VERSION 5.7 ;
BUSBITCHARS "[]" ;
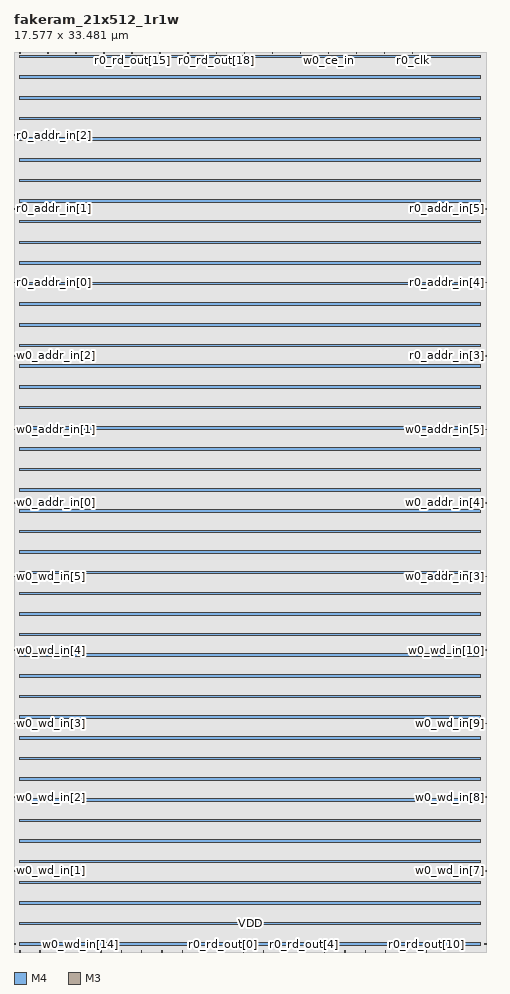
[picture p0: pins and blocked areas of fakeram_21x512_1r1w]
MACRO fakeram_21x512_1r1w
  FOREIGN fakeram_21x512_1r1w 0 0 ;
  SYMMETRY X Y R90 ;
  SIZE 17.577 BY 33.481 ;
  CLASS BLOCK ;
  PIN w0_wd_in[0]
    DIRECTION INPUT ;
    USE SIGNAL ;
    SHAPE ABUTMENT ;
    PORT
      LAYER M4 ;
      RECT 0.000 0.276 0.072 0.300 ;
    END
  END w0_wd_in[0]
  PIN w0_wd_in[1]
    DIRECTION INPUT ;
    USE SIGNAL ;
    SHAPE ABUTMENT ;
    PORT
      LAYER M4 ;
      RECT 0.000 3.012 0.072 3.036 ;
    END
  END w0_wd_in[1]
  PIN w0_wd_in[2]
    DIRECTION INPUT ;
    USE SIGNAL ;
    SHAPE ABUTMENT ;
    PORT
      LAYER M4 ;
      RECT 0.000 5.748 0.072 5.772 ;
    END
  END w0_wd_in[2]
  PIN w0_wd_in[3]
    DIRECTION INPUT ;
    USE SIGNAL ;
    SHAPE ABUTMENT ;
    PORT
      LAYER M4 ;
      RECT 0.000 8.484 0.072 8.508 ;
    END
  END w0_wd_in[3]
  PIN w0_wd_in[4]
    DIRECTION INPUT ;
    USE SIGNAL ;
    SHAPE ABUTMENT ;
    PORT
      LAYER M4 ;
      RECT 0.000 11.220 0.072 11.244 ;
    END
  END w0_wd_in[4]
  PIN w0_wd_in[5]
    DIRECTION INPUT ;
    USE SIGNAL ;
    SHAPE ABUTMENT ;
    PORT
      LAYER M4 ;
      RECT 0.000 13.956 0.072 13.980 ;
    END
  END w0_wd_in[5]
  PIN w0_wd_in[6]
    DIRECTION INPUT ;
    USE SIGNAL ;
    SHAPE ABUTMENT ;
    PORT
      LAYER M4 ;
      RECT 17.505 0.276 17.577 0.300 ;
    END
  END w0_wd_in[6]
  PIN w0_wd_in[7]
    DIRECTION INPUT ;
    USE SIGNAL ;
    SHAPE ABUTMENT ;
    PORT
      LAYER M4 ;
      RECT 17.505 3.012 17.577 3.036 ;
    END
  END w0_wd_in[7]
  PIN w0_wd_in[8]
    DIRECTION INPUT ;
    USE SIGNAL ;
    SHAPE ABUTMENT ;
    PORT
      LAYER M4 ;
      RECT 17.505 5.748 17.577 5.772 ;
    END
  END w0_wd_in[8]
  PIN w0_wd_in[9]
    DIRECTION INPUT ;
    USE SIGNAL ;
    SHAPE ABUTMENT ;
    PORT
      LAYER M4 ;
      RECT 17.505 8.484 17.577 8.508 ;
    END
  END w0_wd_in[9]
  PIN w0_wd_in[10]
    DIRECTION INPUT ;
    USE SIGNAL ;
    SHAPE ABUTMENT ;
    PORT
      LAYER M4 ;
      RECT 17.505 11.220 17.577 11.244 ;
    END
  END w0_wd_in[10]
  PIN w0_wd_in[11]
    DIRECTION INPUT ;
    USE SIGNAL ;
    SHAPE ABUTMENT ;
    PORT
      LAYER M3 ;
      RECT 0.207 0.000 0.225 0.054 ;
    END
  END w0_wd_in[11]
  PIN w0_wd_in[12]
    DIRECTION INPUT ;
    USE SIGNAL ;
    SHAPE ABUTMENT ;
    PORT
      LAYER M3 ;
      RECT 0.963 0.000 0.981 0.054 ;
    END
  END w0_wd_in[12]
  PIN w0_wd_in[13]
    DIRECTION INPUT ;
    USE SIGNAL ;
    SHAPE ABUTMENT ;
    PORT
      LAYER M3 ;
      RECT 1.719 0.000 1.737 0.054 ;
    END
  END w0_wd_in[13]
  PIN w0_wd_in[14]
    DIRECTION INPUT ;
    USE SIGNAL ;
    SHAPE ABUTMENT ;
    PORT
      LAYER M3 ;
      RECT 2.475 0.000 2.493 0.054 ;
    END
  END w0_wd_in[14]
  PIN w0_wd_in[15]
    DIRECTION INPUT ;
    USE SIGNAL ;
    SHAPE ABUTMENT ;
    PORT
      LAYER M3 ;
      RECT 3.231 0.000 3.249 0.054 ;
    END
  END w0_wd_in[15]
  PIN w0_wd_in[16]
    DIRECTION INPUT ;
    USE SIGNAL ;
    SHAPE ABUTMENT ;
    PORT
      LAYER M3 ;
      RECT 3.987 0.000 4.005 0.054 ;
    END
  END w0_wd_in[16]
  PIN w0_wd_in[17]
    DIRECTION INPUT ;
    USE SIGNAL ;
    SHAPE ABUTMENT ;
    PORT
      LAYER M3 ;
      RECT 4.743 0.000 4.761 0.054 ;
    END
  END w0_wd_in[17]
  PIN w0_wd_in[18]
    DIRECTION INPUT ;
    USE SIGNAL ;
    SHAPE ABUTMENT ;
    PORT
      LAYER M3 ;
      RECT 5.499 0.000 5.517 0.054 ;
    END
  END w0_wd_in[18]
  PIN w0_wd_in[19]
    DIRECTION INPUT ;
    USE SIGNAL ;
    SHAPE ABUTMENT ;
    PORT
      LAYER M3 ;
      RECT 6.255 0.000 6.273 0.054 ;
    END
  END w0_wd_in[19]
  PIN w0_wd_in[20]
    DIRECTION INPUT ;
    USE SIGNAL ;
    SHAPE ABUTMENT ;
    PORT
      LAYER M3 ;
      RECT 7.011 0.000 7.029 0.054 ;
    END
  END w0_wd_in[20]
  PIN r0_rd_out[0]
    DIRECTION OUTPUT ;
    USE SIGNAL ;
    SHAPE ABUTMENT ;
    PORT
      LAYER M3 ;
      RECT 7.767 0.000 7.785 0.054 ;
    END
  END r0_rd_out[0]
  PIN r0_rd_out[1]
    DIRECTION OUTPUT ;
    USE SIGNAL ;
    SHAPE ABUTMENT ;
    PORT
      LAYER M3 ;
      RECT 8.523 0.000 8.541 0.054 ;
    END
  END r0_rd_out[1]
  PIN r0_rd_out[2]
    DIRECTION OUTPUT ;
    USE SIGNAL ;
    SHAPE ABUTMENT ;
    PORT
      LAYER M3 ;
      RECT 9.279 0.000 9.297 0.054 ;
    END
  END r0_rd_out[2]
  PIN r0_rd_out[3]
    DIRECTION OUTPUT ;
    USE SIGNAL ;
    SHAPE ABUTMENT ;
    PORT
      LAYER M3 ;
      RECT 10.035 0.000 10.053 0.054 ;
    END
  END r0_rd_out[3]
  PIN r0_rd_out[4]
    DIRECTION OUTPUT ;
    USE SIGNAL ;
    SHAPE ABUTMENT ;
    PORT
      LAYER M3 ;
      RECT 10.791 0.000 10.809 0.054 ;
    END
  END r0_rd_out[4]
  PIN r0_rd_out[5]
    DIRECTION OUTPUT ;
    USE SIGNAL ;
    SHAPE ABUTMENT ;
    PORT
      LAYER M3 ;
      RECT 11.547 0.000 11.565 0.054 ;
    END
  END r0_rd_out[5]
  PIN r0_rd_out[6]
    DIRECTION OUTPUT ;
    USE SIGNAL ;
    SHAPE ABUTMENT ;
    PORT
      LAYER M3 ;
      RECT 12.303 0.000 12.321 0.054 ;
    END
  END r0_rd_out[6]
  PIN r0_rd_out[7]
    DIRECTION OUTPUT ;
    USE SIGNAL ;
    SHAPE ABUTMENT ;
    PORT
      LAYER M3 ;
      RECT 13.059 0.000 13.077 0.054 ;
    END
  END r0_rd_out[7]
  PIN r0_rd_out[8]
    DIRECTION OUTPUT ;
    USE SIGNAL ;
    SHAPE ABUTMENT ;
    PORT
      LAYER M3 ;
      RECT 13.815 0.000 13.833 0.054 ;
    END
  END r0_rd_out[8]
  PIN r0_rd_out[9]
    DIRECTION OUTPUT ;
    USE SIGNAL ;
    SHAPE ABUTMENT ;
    PORT
      LAYER M3 ;
      RECT 14.571 0.000 14.589 0.054 ;
    END
  END r0_rd_out[9]
  PIN r0_rd_out[10]
    DIRECTION OUTPUT ;
    USE SIGNAL ;
    SHAPE ABUTMENT ;
    PORT
      LAYER M3 ;
      RECT 15.327 0.000 15.345 0.054 ;
    END
  END r0_rd_out[10]
  PIN r0_rd_out[11]
    DIRECTION OUTPUT ;
    USE SIGNAL ;
    SHAPE ABUTMENT ;
    PORT
      LAYER M3 ;
      RECT 0.207 33.427 0.225 33.481 ;
    END
  END r0_rd_out[11]
  PIN r0_rd_out[12]
    DIRECTION OUTPUT ;
    USE SIGNAL ;
    SHAPE ABUTMENT ;
    PORT
      LAYER M3 ;
      RECT 1.251 33.427 1.269 33.481 ;
    END
  END r0_rd_out[12]
  PIN r0_rd_out[13]
    DIRECTION OUTPUT ;
    USE SIGNAL ;
    SHAPE ABUTMENT ;
    PORT
      LAYER M3 ;
      RECT 2.295 33.427 2.313 33.481 ;
    END
  END r0_rd_out[13]
  PIN r0_rd_out[14]
    DIRECTION OUTPUT ;
    USE SIGNAL ;
    SHAPE ABUTMENT ;
    PORT
      LAYER M3 ;
      RECT 3.339 33.427 3.357 33.481 ;
    END
  END r0_rd_out[14]
  PIN r0_rd_out[15]
    DIRECTION OUTPUT ;
    USE SIGNAL ;
    SHAPE ABUTMENT ;
    PORT
      LAYER M3 ;
      RECT 4.383 33.427 4.401 33.481 ;
    END
  END r0_rd_out[15]
  PIN r0_rd_out[16]
    DIRECTION OUTPUT ;
    USE SIGNAL ;
    SHAPE ABUTMENT ;
    PORT
      LAYER M3 ;
      RECT 5.427 33.427 5.445 33.481 ;
    END
  END r0_rd_out[16]
  PIN r0_rd_out[17]
    DIRECTION OUTPUT ;
    USE SIGNAL ;
    SHAPE ABUTMENT ;
    PORT
      LAYER M3 ;
      RECT 6.471 33.427 6.489 33.481 ;
    END
  END r0_rd_out[17]
  PIN r0_rd_out[18]
    DIRECTION OUTPUT ;
    USE SIGNAL ;
    SHAPE ABUTMENT ;
    PORT
      LAYER M3 ;
      RECT 7.515 33.427 7.533 33.481 ;
    END
  END r0_rd_out[18]
  PIN r0_rd_out[19]
    DIRECTION OUTPUT ;
    USE SIGNAL ;
    SHAPE ABUTMENT ;
    PORT
      LAYER M3 ;
      RECT 8.559 33.427 8.577 33.481 ;
    END
  END r0_rd_out[19]
  PIN r0_rd_out[20]
    DIRECTION OUTPUT ;
    USE SIGNAL ;
    SHAPE ABUTMENT ;
    PORT
      LAYER M3 ;
      RECT 9.603 33.427 9.621 33.481 ;
    END
  END r0_rd_out[20]
  PIN w0_addr_in[0]
    DIRECTION INPUT ;
    USE SIGNAL ;
    SHAPE ABUTMENT ;
    PORT
      LAYER M4 ;
      RECT 0.000 16.692 0.072 16.716 ;
    END
  END w0_addr_in[0]
  PIN w0_addr_in[1]
    DIRECTION INPUT ;
    USE SIGNAL ;
    SHAPE ABUTMENT ;
    PORT
      LAYER M4 ;
      RECT 0.000 19.428 0.072 19.452 ;
    END
  END w0_addr_in[1]
  PIN w0_addr_in[2]
    DIRECTION INPUT ;
    USE SIGNAL ;
    SHAPE ABUTMENT ;
    PORT
      LAYER M4 ;
      RECT 0.000 22.164 0.072 22.188 ;
    END
  END w0_addr_in[2]
  PIN w0_addr_in[3]
    DIRECTION INPUT ;
    USE SIGNAL ;
    SHAPE ABUTMENT ;
    PORT
      LAYER M4 ;
      RECT 17.505 13.956 17.577 13.980 ;
    END
  END w0_addr_in[3]
  PIN w0_addr_in[4]
    DIRECTION INPUT ;
    USE SIGNAL ;
    SHAPE ABUTMENT ;
    PORT
      LAYER M4 ;
      RECT 17.505 16.692 17.577 16.716 ;
    END
  END w0_addr_in[4]
  PIN w0_addr_in[5]
    DIRECTION INPUT ;
    USE SIGNAL ;
    SHAPE ABUTMENT ;
    PORT
      LAYER M4 ;
      RECT 17.505 19.428 17.577 19.452 ;
    END
  END w0_addr_in[5]
  PIN r0_addr_in[0]
    DIRECTION INPUT ;
    USE SIGNAL ;
    SHAPE ABUTMENT ;
    PORT
      LAYER M4 ;
      RECT 0.000 24.900 0.072 24.924 ;
    END
  END r0_addr_in[0]
  PIN r0_addr_in[1]
    DIRECTION INPUT ;
    USE SIGNAL ;
    SHAPE ABUTMENT ;
    PORT
      LAYER M4 ;
      RECT 0.000 27.636 0.072 27.660 ;
    END
  END r0_addr_in[1]
  PIN r0_addr_in[2]
    DIRECTION INPUT ;
    USE SIGNAL ;
    SHAPE ABUTMENT ;
    PORT
      LAYER M4 ;
      RECT 0.000 30.372 0.072 30.396 ;
    END
  END r0_addr_in[2]
  PIN r0_addr_in[3]
    DIRECTION INPUT ;
    USE SIGNAL ;
    SHAPE ABUTMENT ;
    PORT
      LAYER M4 ;
      RECT 17.505 22.164 17.577 22.188 ;
    END
  END r0_addr_in[3]
  PIN r0_addr_in[4]
    DIRECTION INPUT ;
    USE SIGNAL ;
    SHAPE ABUTMENT ;
    PORT
      LAYER M4 ;
      RECT 17.505 24.900 17.577 24.924 ;
    END
  END r0_addr_in[4]
  PIN r0_addr_in[5]
    DIRECTION INPUT ;
    USE SIGNAL ;
    SHAPE ABUTMENT ;
    PORT
      LAYER M4 ;
      RECT 17.505 27.636 17.577 27.660 ;
    END
  END r0_addr_in[5]
  PIN w0_we_in
    DIRECTION INPUT ;
    USE SIGNAL ;
    SHAPE ABUTMENT ;
    PORT
      LAYER M3 ;
      RECT 10.647 33.427 10.665 33.481 ;
    END
  END w0_we_in
  PIN w0_ce_in
    DIRECTION INPUT ;
    USE SIGNAL ;
    SHAPE ABUTMENT ;
    PORT
      LAYER M3 ;
      RECT 11.691 33.427 11.709 33.481 ;
    END
  END w0_ce_in
  PIN w0_clk
    DIRECTION INPUT ;
    USE SIGNAL ;
    SHAPE ABUTMENT ;
    PORT
      LAYER M3 ;
      RECT 12.735 33.427 12.753 33.481 ;
    END
  END w0_clk
  PIN r0_ce_in
    DIRECTION INPUT ;
    USE SIGNAL ;
    SHAPE ABUTMENT ;
    PORT
      LAYER M3 ;
      RECT 13.779 33.427 13.797 33.481 ;
    END
  END r0_ce_in
  PIN r0_clk
    DIRECTION INPUT ;
    USE SIGNAL ;
    SHAPE ABUTMENT ;
    PORT
      LAYER M3 ;
      RECT 14.823 33.427 14.841 33.481 ;
    END
  END r0_clk
  PIN VSS
    DIRECTION INOUT ;
    USE GROUND ;
    PORT
      LAYER M4 ;
      RECT 0.216 0.240 17.361 0.336 ;
      RECT 0.216 1.008 17.361 1.104 ;
      RECT 0.216 1.776 17.361 1.872 ;
      RECT 0.216 2.544 17.361 2.640 ;
      RECT 0.216 3.312 17.361 3.408 ;
      RECT 0.216 4.080 17.361 4.176 ;
      RECT 0.216 4.848 17.361 4.944 ;
      RECT 0.216 5.616 17.361 5.712 ;
      RECT 0.216 6.384 17.361 6.480 ;
      RECT 0.216 7.152 17.361 7.248 ;
      RECT 0.216 7.920 17.361 8.016 ;
      RECT 0.216 8.688 17.361 8.784 ;
      RECT 0.216 9.456 17.361 9.552 ;
      RECT 0.216 10.224 17.361 10.320 ;
      RECT 0.216 10.992 17.361 11.088 ;
      RECT 0.216 11.760 17.361 11.856 ;
      RECT 0.216 12.528 17.361 12.624 ;
      RECT 0.216 13.296 17.361 13.392 ;
      RECT 0.216 14.064 17.361 14.160 ;
      RECT 0.216 14.832 17.361 14.928 ;
      RECT 0.216 15.600 17.361 15.696 ;
      RECT 0.216 16.368 17.361 16.464 ;
      RECT 0.216 17.136 17.361 17.232 ;
      RECT 0.216 17.904 17.361 18.000 ;
      RECT 0.216 18.672 17.361 18.768 ;
      RECT 0.216 19.440 17.361 19.536 ;
      RECT 0.216 20.208 17.361 20.304 ;
      RECT 0.216 20.976 17.361 21.072 ;
      RECT 0.216 21.744 17.361 21.840 ;
      RECT 0.216 22.512 17.361 22.608 ;
      RECT 0.216 23.280 17.361 23.376 ;
      RECT 0.216 24.048 17.361 24.144 ;
      RECT 0.216 24.816 17.361 24.912 ;
      RECT 0.216 25.584 17.361 25.680 ;
      RECT 0.216 26.352 17.361 26.448 ;
      RECT 0.216 27.120 17.361 27.216 ;
      RECT 0.216 27.888 17.361 27.984 ;
      RECT 0.216 28.656 17.361 28.752 ;
      RECT 0.216 29.424 17.361 29.520 ;
      RECT 0.216 30.192 17.361 30.288 ;
      RECT 0.216 30.960 17.361 31.056 ;
      RECT 0.216 31.728 17.361 31.824 ;
      RECT 0.216 32.496 17.361 32.592 ;
      RECT 0.216 33.264 17.361 33.360 ;
    END
  END VSS
  PIN VDD
    DIRECTION INOUT ;
    USE POWER ;
    PORT
      LAYER M4 ;
      RECT 0.216 0.240 17.361 0.336 ;
      RECT 0.216 1.008 17.361 1.104 ;
      RECT 0.216 1.776 17.361 1.872 ;
      RECT 0.216 2.544 17.361 2.640 ;
      RECT 0.216 3.312 17.361 3.408 ;
      RECT 0.216 4.080 17.361 4.176 ;
      RECT 0.216 4.848 17.361 4.944 ;
      RECT 0.216 5.616 17.361 5.712 ;
      RECT 0.216 6.384 17.361 6.480 ;
      RECT 0.216 7.152 17.361 7.248 ;
      RECT 0.216 7.920 17.361 8.016 ;
      RECT 0.216 8.688 17.361 8.784 ;
      RECT 0.216 9.456 17.361 9.552 ;
      RECT 0.216 10.224 17.361 10.320 ;
      RECT 0.216 10.992 17.361 11.088 ;
      RECT 0.216 11.760 17.361 11.856 ;
      RECT 0.216 12.528 17.361 12.624 ;
      RECT 0.216 13.296 17.361 13.392 ;
      RECT 0.216 14.064 17.361 14.160 ;
      RECT 0.216 14.832 17.361 14.928 ;
      RECT 0.216 15.600 17.361 15.696 ;
      RECT 0.216 16.368 17.361 16.464 ;
      RECT 0.216 17.136 17.361 17.232 ;
      RECT 0.216 17.904 17.361 18.000 ;
      RECT 0.216 18.672 17.361 18.768 ;
      RECT 0.216 19.440 17.361 19.536 ;
      RECT 0.216 20.208 17.361 20.304 ;
      RECT 0.216 20.976 17.361 21.072 ;
      RECT 0.216 21.744 17.361 21.840 ;
      RECT 0.216 22.512 17.361 22.608 ;
      RECT 0.216 23.280 17.361 23.376 ;
      RECT 0.216 24.048 17.361 24.144 ;
      RECT 0.216 24.816 17.361 24.912 ;
      RECT 0.216 25.584 17.361 25.680 ;
      RECT 0.216 26.352 17.361 26.448 ;
      RECT 0.216 27.120 17.361 27.216 ;
      RECT 0.216 27.888 17.361 27.984 ;
      RECT 0.216 28.656 17.361 28.752 ;
      RECT 0.216 29.424 17.361 29.520 ;
      RECT 0.216 30.192 17.361 30.288 ;
      RECT 0.216 30.960 17.361 31.056 ;
      RECT 0.216 31.728 17.361 31.824 ;
      RECT 0.216 32.496 17.361 32.592 ;
      RECT 0.216 33.264 17.361 33.360 ;
    END
  END VDD
  OBS
    LAYER M1 ;
    RECT 0 0 17.577 33.481 ;
    LAYER M2 ;
    RECT 0 0 17.577 33.481 ;
    LAYER M3 ;
    RECT 0 0 17.577 33.481 ;
    LAYER M4 ;
    RECT 0 0 17.577 33.481 ;
  END
END fakeram_21x512_1r1w

END LIBRARY
